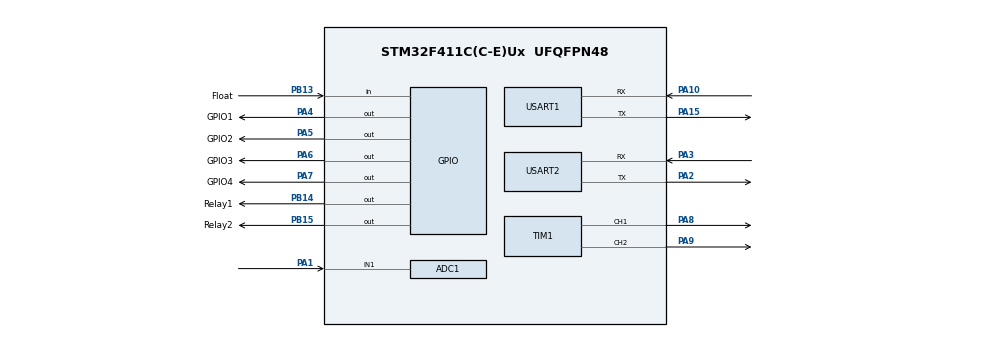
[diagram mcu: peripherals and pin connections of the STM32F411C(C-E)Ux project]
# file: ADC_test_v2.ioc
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ADC1.Channel-1\#ChannelRegularConversion=ADC_CHANNEL_1
ADC1.NbrOfConversionFlag=1
ADC1.Rank-1\#ChannelRegularConversion=1
ADC1.SamplingTime-1\#ChannelRegularConversion=ADC_SAMPLETIME_3CYCLES
ADC1.master=1
Mcu.Family=STM32F4
Mcu.Name=STM32F411C(C-E)Ux
Mcu.Package=UFQFPN48
NVIC.PriorityGroup=NVIC_PRIORITYGROUP_4
PA1.Signal=ADCx_IN1
PA10.Mode=Asynchronous
PA10.Signal=USART1_RX
PA13.Mode=Trace_Asynchronous_SW
PA13.Signal=SYS_JTMS-SWDIO
PA14.Mode=Trace_Asynchronous_SW
PA14.Signal=SYS_JTCK-SWCLK
PA15.Mode=Asynchronous
PA15.Signal=USART1_TX
PA2.Mode=Asynchronous
PA2.Signal=USART2_TX
PA3.Mode=Asynchronous
PA3.Signal=USART2_RX
PA4.GPIO_Label=GPIO1
PA4.Signal=GPIO_Output
PA5.GPIO_Label=GPIO2
PA5.Signal=GPIO_Output
PA6.GPIO_Label=GPIO3
PA6.Signal=GPIO_Output
PA7.GPIO_Label=GPIO4
PA7.Signal=GPIO_Output
PA8.Signal=S_TIM1_CH1
PA9.Signal=S_TIM1_CH2
PB13.GPIO_Label=Float
PB13.Signal=GPIO_Input
PB14.GPIO_Label=Relay1
PB14.Signal=GPIO_Output
PB15.GPIO_Label=Relay2
PB15.Signal=GPIO_Output
PB3.Mode=Trace_Asynchronous_SW
PB3.Signal=SYS_JTDO-SWO
ProjectManager.HeapSize=0x200
ProjectManager.StackSize=0x400
ProjectManager.TargetToolchain=STM32CubeIDE
RCC.AHBFreq_Value=16000000
RCC.APB1Freq_Value=16000000
RCC.APB2Freq_Value=16000000
RCC.CortexFreq_Value=16000000
RCC.HSE_VALUE=25000000
RCC.HSI_VALUE=16000000
RCC.LSE_VALUE=32768
RCC.SYSCLKFreq_VALUE=16000000
RCC.VCOOutputFreq_Value=192000000
SH.ADCx_IN1.0=ADC1_IN1,IN1
SH.S_TIM1_CH1.0=TIM1_CH1,PWM Generation1 CH1
SH.S_TIM1_CH2.0=TIM1_CH2,PWM Generation2 CH2
TIM1.Channel-PWM\ Generation1\ CH1=TIM_CHANNEL_1
TIM1.Channel-PWM\ Generation2\ CH2=TIM_CHANNEL_2
USART1.VirtualMode=VM_ASYNC
USART2.VirtualMode=VM_ASYNC
board=custom

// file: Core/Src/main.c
/* USER CODE BEGIN Header */
/**
  ******************************************************************************
  * @file           : main.c
  * @brief          : Main program body
  ******************************************************************************
  * @attention
  *
  * Copyright (c) 2026 STMicroelectronics.
  * All rights reserved.
  *
  * This software is licensed under terms that can be found in the LICENSE file
  * in the root directory of this software component.
  * If no LICENSE file comes with this software, it is provided AS-IS.
  *
  ******************************************************************************
  */
/* USER CODE END Header */
#include "main.h"
/* USER CODE BEGIN Includes */
#include <stdio.h>
// test comment
/* USER CODE END Includes */

ADC_HandleTypeDef hadc1;

TIM_HandleTypeDef htim1;

UART_HandleTypeDef huart1;
UART_HandleTypeDef huart2;

void SystemClock_Config(void);
static void MX_GPIO_Init(void);
static void MX_ADC1_Init(void);
static void MX_TIM1_Init(void);
static void MX_USART1_UART_Init(void);
static void MX_USART2_UART_Init(void);

int main(void)
{

  /* MCU Configuration--------------------------------------------------------*/

  /* Reset of all peripherals, Initializes the Flash interface and the Systick. */
  HAL_Init();

  /* Configure the system clock */
  SystemClock_Config();

  /* Initialize all configured peripherals */
  MX_GPIO_Init();
  MX_ADC1_Init();
  MX_TIM1_Init();
  MX_USART1_UART_Init();
  MX_USART2_UART_Init();

  /* Infinite loop */
  /* USER CODE BEGIN WHILE */
  uint32_t adc_value = 0;
  char cInstructions[100];
  int len = snprintf(cInstructions, sizeof(cInstructions), "ADC reading %lu \r\n", adc_value);;
  HAL_UART_Transmit(&huart1, (uint8_t*)cInstructions, len, 100);
  /* 1. Start the ADC conversion */
  HAL_ADC_Start(&hadc1);
  while (1)
  {
	/* 2. Wait for the conversion to complete (100ms timeout) */
	if (HAL_ADC_PollForConversion(&hadc1, 100) == HAL_OK)
	{
	  /* 3. Get the converted digital value */
	  adc_value = HAL_ADC_GetValue(&hadc1);
	}

	/* 4. Stop the ADC */
	HAL_ADC_Stop(&hadc1);

	/* Wait 1000ms (1 second) before the next reading */
//	HAL_Delay(100);
	len = snprintf(cInstructions, sizeof(cInstructions), "ADC reading %lu \r\n", adc_value);

	HAL_UART_Transmit(&huart1, (uint8_t*)cInstructions, len, 100);
    /* USER CODE END WHILE */

  }
}

void SystemClock_Config(void)
{
  RCC_OscInitTypeDef RCC_OscInitStruct = {0};
  RCC_ClkInitTypeDef RCC_ClkInitStruct = {0};

  /** Configure the main internal regulator output voltage
  */
  __HAL_RCC_PWR_CLK_ENABLE();
  __HAL_PWR_VOLTAGESCALING_CONFIG(PWR_REGULATOR_VOLTAGE_SCALE1);

  /** Initializes the RCC Oscillators according to the specified parameters
  * in the RCC_OscInitTypeDef structure.
  */
  RCC_OscInitStruct.OscillatorType = RCC_OSCILLATORTYPE_HSI;
  RCC_OscInitStruct.HSIState = RCC_HSI_ON;
  RCC_OscInitStruct.HSICalibrationValue = RCC_HSICALIBRATION_DEFAULT;
  RCC_OscInitStruct.PLL.PLLState = RCC_PLL_ON;
  RCC_OscInitStruct.PLL.PLLSource = RCC_PLLSOURCE_HSI;
  RCC_OscInitStruct.PLL.PLLM = 16;
  RCC_OscInitStruct.PLL.PLLN = 192;
  RCC_OscInitStruct.PLL.PLLP = RCC_PLLP_DIV2;
  RCC_OscInitStruct.PLL.PLLQ = 4;
  if (HAL_RCC_OscConfig(&RCC_OscInitStruct) != HAL_OK)
  {
    Error_Handler();
  }

  /** Initializes the CPU, AHB and APB buses clocks
  */
  RCC_ClkInitStruct.ClockType = RCC_CLOCKTYPE_HCLK|RCC_CLOCKTYPE_SYSCLK
                              |RCC_CLOCKTYPE_PCLK1|RCC_CLOCKTYPE_PCLK2;
  RCC_ClkInitStruct.SYSCLKSource = RCC_SYSCLKSOURCE_PLLCLK;
  RCC_ClkInitStruct.AHBCLKDivider = RCC_SYSCLK_DIV1;
  RCC_ClkInitStruct.APB1CLKDivider = RCC_HCLK_DIV2;
  RCC_ClkInitStruct.APB2CLKDivider = RCC_HCLK_DIV1;

  if (HAL_RCC_ClockConfig(&RCC_ClkInitStruct, FLASH_LATENCY_3) != HAL_OK)
  {
    Error_Handler();
  }
}

static void MX_ADC1_Init(void)
{

  ADC_ChannelConfTypeDef sConfig = {0};

  /** Configure the global features of the ADC (Clock, Resolution, Data Alignment and number of conversion)
  */
  hadc1.Instance = ADC1;
  hadc1.Init.ClockPrescaler = ADC_CLOCK_SYNC_PCLK_DIV4;
  hadc1.Init.Resolution = ADC_RESOLUTION_12B;
  hadc1.Init.ScanConvMode = DISABLE;
  hadc1.Init.ContinuousConvMode = DISABLE;
  hadc1.Init.DiscontinuousConvMode = DISABLE;
  hadc1.Init.ExternalTrigConvEdge = ADC_EXTERNALTRIGCONVEDGE_NONE;
  hadc1.Init.ExternalTrigConv = ADC_SOFTWARE_START;
  hadc1.Init.DataAlign = ADC_DATAALIGN_RIGHT;
  hadc1.Init.NbrOfConversion = 1;
  hadc1.Init.DMAContinuousRequests = DISABLE;
  hadc1.Init.EOCSelection = ADC_EOC_SINGLE_CONV;
  if (HAL_ADC_Init(&hadc1) != HAL_OK)
  {
    Error_Handler();
  }

  /** Configure for the selected ADC regular channel its corresponding rank in the sequencer and its sample time.
  */
  sConfig.Channel = ADC_CHANNEL_1;
  sConfig.Rank = 1;
  sConfig.SamplingTime = ADC_SAMPLETIME_3CYCLES;
  if (HAL_ADC_ConfigChannel(&hadc1, &sConfig) != HAL_OK)
  {
    Error_Handler();
  }

}

static void MX_TIM1_Init(void)
{

  TIM_MasterConfigTypeDef sMasterConfig = {0};
  TIM_OC_InitTypeDef sConfigOC = {0};
  TIM_BreakDeadTimeConfigTypeDef sBreakDeadTimeConfig = {0};

  htim1.Instance = TIM1;
  htim1.Init.Prescaler = 0;
  htim1.Init.CounterMode = TIM_COUNTERMODE_UP;
  htim1.Init.Period = 65535;
  htim1.Init.ClockDivision = TIM_CLOCKDIVISION_DIV1;
  htim1.Init.RepetitionCounter = 0;
  htim1.Init.AutoReloadPreload = TIM_AUTORELOAD_PRELOAD_DISABLE;
  if (HAL_TIM_PWM_Init(&htim1) != HAL_OK)
  {
    Error_Handler();
  }
  sMasterConfig.MasterOutputTrigger = TIM_TRGO_RESET;
  sMasterConfig.MasterSlaveMode = TIM_MASTERSLAVEMODE_DISABLE;
  if (HAL_TIMEx_MasterConfigSynchronization(&htim1, &sMasterConfig) != HAL_OK)
  {
    Error_Handler();
  }
  sConfigOC.OCMode = TIM_OCMODE_PWM1;
  sConfigOC.Pulse = 0;
  sConfigOC.OCPolarity = TIM_OCPOLARITY_HIGH;
  sConfigOC.OCNPolarity = TIM_OCNPOLARITY_HIGH;
  sConfigOC.OCFastMode = TIM_OCFAST_DISABLE;
  sConfigOC.OCIdleState = TIM_OCIDLESTATE_RESET;
  sConfigOC.OCNIdleState = TIM_OCNIDLESTATE_RESET;
  if (HAL_TIM_PWM_ConfigChannel(&htim1, &sConfigOC, TIM_CHANNEL_1) != HAL_OK)
  {
    Error_Handler();
  }
  if (HAL_TIM_PWM_ConfigChannel(&htim1, &sConfigOC, TIM_CHANNEL_2) != HAL_OK)
  {
    Error_Handler();
  }
  sBreakDeadTimeConfig.OffStateRunMode = TIM_OSSR_DISABLE;
  sBreakDeadTimeConfig.OffStateIDLEMode = TIM_OSSI_DISABLE;
  sBreakDeadTimeConfig.LockLevel = TIM_LOCKLEVEL_OFF;
  sBreakDeadTimeConfig.DeadTime = 0;
  sBreakDeadTimeConfig.BreakState = TIM_BREAK_DISABLE;
  sBreakDeadTimeConfig.BreakPolarity = TIM_BREAKPOLARITY_HIGH;
  sBreakDeadTimeConfig.AutomaticOutput = TIM_AUTOMATICOUTPUT_DISABLE;
  if (HAL_TIMEx_ConfigBreakDeadTime(&htim1, &sBreakDeadTimeConfig) != HAL_OK)
  {
    Error_Handler();
  }
  HAL_TIM_MspPostInit(&htim1);

}

static void MX_USART1_UART_Init(void)
{

  huart1.Instance = USART1;
  huart1.Init.BaudRate = 115200;
  huart1.Init.WordLength = UART_WORDLENGTH_8B;
  huart1.Init.StopBits = UART_STOPBITS_1;
  huart1.Init.Parity = UART_PARITY_NONE;
  huart1.Init.Mode = UART_MODE_TX_RX;
  huart1.Init.HwFlowCtl = UART_HWCONTROL_NONE;
  huart1.Init.OverSampling = UART_OVERSAMPLING_16;
  if (HAL_UART_Init(&huart1) != HAL_OK)
  {
    Error_Handler();
  }

}

static void MX_USART2_UART_Init(void)
{

  huart2.Instance = USART2;
  huart2.Init.BaudRate = 115200;
  huart2.Init.WordLength = UART_WORDLENGTH_8B;
  huart2.Init.StopBits = UART_STOPBITS_1;
  huart2.Init.Parity = UART_PARITY_NONE;
  huart2.Init.Mode = UART_MODE_TX_RX;
  huart2.Init.HwFlowCtl = UART_HWCONTROL_NONE;
  huart2.Init.OverSampling = UART_OVERSAMPLING_16;
  if (HAL_UART_Init(&huart2) != HAL_OK)
  {
    Error_Handler();
  }

}

static void MX_GPIO_Init(void)
{
  GPIO_InitTypeDef GPIO_InitStruct = {0};

  /* GPIO Ports Clock Enable */
  __HAL_RCC_GPIOA_CLK_ENABLE();
  __HAL_RCC_GPIOB_CLK_ENABLE();

  /*Configure GPIO pin Output Level */
  HAL_GPIO_WritePin(GPIOA, GPIO1_Pin|GPIO2_Pin|GPIO3_Pin|GPIO4_Pin, GPIO_PIN_RESET);

  /*Configure GPIO pin Output Level */
  HAL_GPIO_WritePin(GPIOB, Relay1_Pin|Relay2_Pin, GPIO_PIN_RESET);

  /*Configure GPIO pins : GPIO1_Pin GPIO2_Pin GPIO3_Pin GPIO4_Pin */
  GPIO_InitStruct.Pin = GPIO1_Pin|GPIO2_Pin|GPIO3_Pin|GPIO4_Pin;
  GPIO_InitStruct.Mode = GPIO_MODE_OUTPUT_PP;
  GPIO_InitStruct.Pull = GPIO_NOPULL;
  GPIO_InitStruct.Speed = GPIO_SPEED_FREQ_LOW;
  HAL_GPIO_Init(GPIOA, &GPIO_InitStruct);

  /*Configure GPIO pin : Float_Pin */
  GPIO_InitStruct.Pin = Float_Pin;
  GPIO_InitStruct.Mode = GPIO_MODE_INPUT;
  GPIO_InitStruct.Pull = GPIO_NOPULL;
  HAL_GPIO_Init(Float_GPIO_Port, &GPIO_InitStruct);

  /*Configure GPIO pins : Relay1_Pin Relay2_Pin */
  GPIO_InitStruct.Pin = Relay1_Pin|Relay2_Pin;
  GPIO_InitStruct.Mode = GPIO_MODE_OUTPUT_PP;
  GPIO_InitStruct.Pull = GPIO_NOPULL;
  GPIO_InitStruct.Speed = GPIO_SPEED_FREQ_LOW;
  HAL_GPIO_Init(GPIOB, &GPIO_InitStruct);

}

void Error_Handler(void)
{
  __disable_irq();
  while (1)
  {
  }
}
